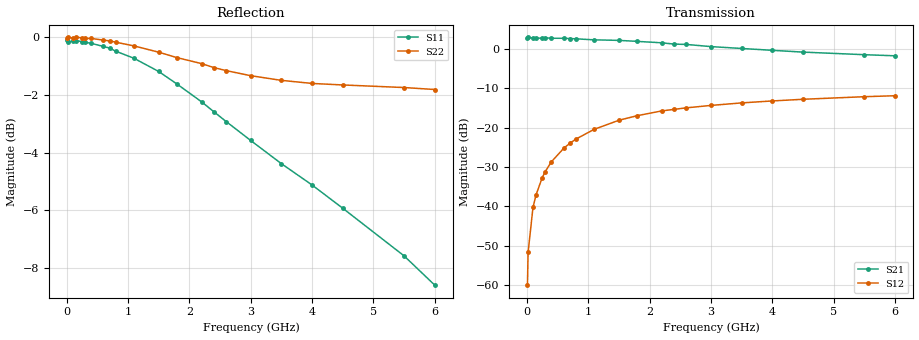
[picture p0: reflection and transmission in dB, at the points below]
! SIEMENS Discrete & RF Semiconductors
! BFY180
! Si NPN RF Bipolar Junction Transistor in MICRO-X
! VCE = 8 V  IC = 0.4 mA
! Common Emitter S-Parameters:  May  1997
# GHz  S  MA  R  50
!  f  S11  S21  S12  S22
! GHz  MAG  ANG  MAG  ANG  MAG  ANG  MAG  ANG
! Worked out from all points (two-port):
!   36 points, 10 MHz to 6 GHz, reference 50 ohm
!   highest |S21| = 2.91 dB at 20 MHz (marker M1); lowest = -1.8 dB at 6 GHz (marker M2)
!   |S21| within 3 dB of the highest: start of sweep to 3.698 GHz
!   lowest |S11| = -8.6 dB at 6 GHz (marker M3), VSWR 2.18, Z = 27.6 - j19.6 ohm
!   |S11| at or under -10 dB: nowhere
!   |S22| runs from -1.8 to 0.0 dB; largest |S21 - S12| = 1.4
!   S11 on the Smith chart (normalised r, x): 10 MHz: open; 700 MHz: 0.69, -5.53; 1.5 GHz: 0.52, -2.53; 2.4 GHz: 0.50, -1.49; 4 GHz: 0.51, -0.82; 6 GHz: 0.55, -0.39
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0.01  0.9886 0.0  1.366 179.6  0.001 83.3  0.9982 -0.3
0.02  0.9801 -0.7  1.398 179.0  0.0026 92.3  0.9999 -0.4
0.1  0.9869 -3.1  1.37 176.3  0.0097 86.8  0.9979 -2.1
0.15  0.9873 -4.5  1.381 174.7  0.014 86.8  0.9997 -3.2
0.25  0.9831 -7.2  1.356 170.9  0.0231 84.9  0.9986 -5.4
0.3  0.9803 -8.6  1.379 168.4  0.0277 83.1  0.9956 -6.5
0.4  0.9766 -11.4  1.363 164.9  0.0368 81.1  0.9958 -8.5
0.6  0.9642 -17.1  1.362 156.5  0.0545 76.2  0.989 -12.7
0.7  0.9581 -20.2  1.352 153.6  0.0632 73.6  0.9861 -14.9
0.8  0.9463 -22.8  1.34 149.4  0.0715 71.6  0.9809 -17.0
1.1  0.9196 -31.0  1.301 139.2  0.0953 64.6  0.9663 -23.1
1.5  0.8725 -41.8  1.281 125.2  0.1239 56.0  0.9425 -31.0
1.8  0.8297 -49.8  1.244 115.0  0.1418 50.4  0.9221 -36.4
2.2  0.7728 -59.1  1.193 101.8  0.1629 42.9  0.9004 -43.4
2.4  0.7429 -63.6  1.149 95.8  0.1706 39.9  0.8862 -46.5
2.6  0.7144 -67.9  1.137 90.0  0.1782 36.9  0.8755 -49.6
3  0.6623 -75.5  1.068 79.3  0.1913 31.1  0.858 -55.5
3.5  0.6037 -83.7  1.011 66.4  0.2059 25.1  0.8421 -62.2
4  0.5544 -92.1  0.958 54.9  0.218 19.4  0.8318 -68.9
4.5  0.5052 -99.5  0.909 44.8  0.2289 14.2  0.8268 -75.7
5.5  0.4176 -115.8  0.843 25.2  0.2468 4.3  0.8183 -89.7
6  0.3715 -124.6  0.816 16.6  0.2539 -0.9  0.8119 -96.7
